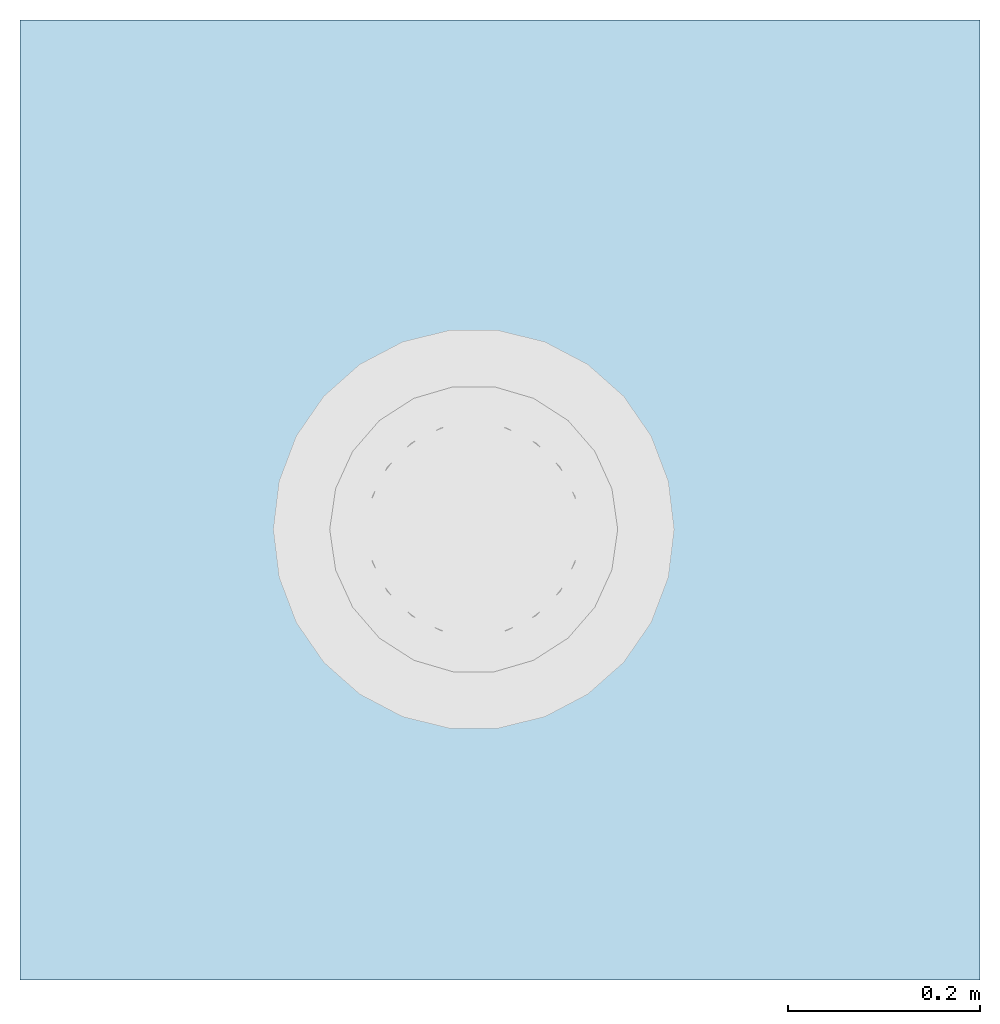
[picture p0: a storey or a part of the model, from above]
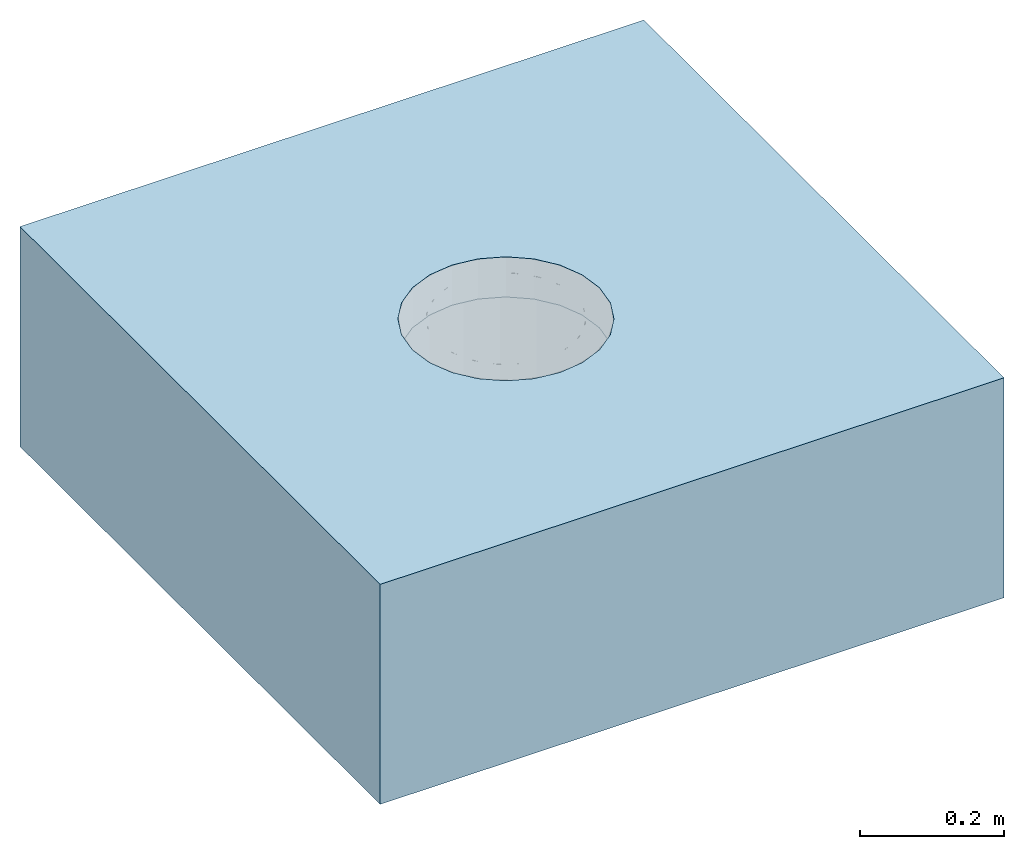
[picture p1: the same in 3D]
Properties of the parts of a building model (IFC2X3)

# File
Description: ViewDefinition [CoordinationView]
File name: Project Number
Time: 2014-10-21T15:01:19
Written by: The EXPRESS Data Manager Version 5.01.0100.02.64mod : 6 Jun 2012
Made in: 20130308_1515(x64) - Exporter 2014.0.2013.0308 - Default UI
Comment: STEP Physical File produced by: The EXPRESS Data Manager Version 5.01.0100.02.64mod : 6 Jun 2012 * Module: EDMstepFileFactory/EDMstandAlone * Creation date: Tue Oct 21 15:01:19 2014 * Host: IN-BLR-PC-0012 * Database: C:\Users\pponnur\AppData\Local\Temp\{F2FFD032-D048-4449-9359-971623433BEB}\ifc * Database version: 5507 * Database creation date: Tue Oct 21 15:01:17 2014 * Schema: IFC2X3 * Model: DataRepository.ifc * Model creation date: Tue Oct 21 15:01:18 2014 * Header model: DataRepository.ifc_HeaderModel * Header model creation date: Tue Oct 21 15:01:18 2014 * EDMuser: sdai-user * EDMgroup: sdai-group * License ID and type: 5605 : Permanent license. Expiry date: * EDMstepFileFactory options: 020000

# IfcProject, Project Number
LongName: Project Name; Phase: Project Status

# IfcSite, Default
RefLatitude: 42, 21, 30, 344238; RefLongitude: -71, -3, -35, -194702; RefElevation: 0 mm

# IfcBuilding
Pset_BuildingCommon - NumberOfStoreys: 1
Other - Project Issue Date: Issue Date; Project Name: Project Name; Project Status: Project Status; Client Name: Owner; Project Address: Enter address here; Project Number: Project Number

# IfcBuildingStorey, Level 1
LongName: Level 1; Elevation: 0 mm
Constraints - Elevation Base: Project Base Point; Elevation: 0 mm
Graphics - Color: 0; Symbol: Level Head - Circle: Level Head - Circle; Line Weight: 1; Symbol at End 1 Default: no; Line Pattern: Grid Line 1/2"; Symbol at End 2 Default: yes
Identity Data - Structural: no; Building Story: yes; Name: Level 1
Dimensions - Computation Height: 0 mm

# IfcFlowTerminal: 408063 Body / 408242 Top - 110mm Dia Outlet, ACO BD Gully 218 Telescopic - Vinyl top - Vertical Outlet with Adhesive Flange - 222 mm:408063 Body / 408242 Top - 110mm Dia Outlet:201730
In: Level 1
Material: Rubber, Nitrile, Stainless Steel AISI 304
Materials and Finishes - Material: Stainless Steel AISI 304
Mechanical - System Classification: Sanitary
Other - Gully Void Start: 0 mm; Floor Void End: -238 mm; 408226 - Raising piece with adhesive bonding flange: no; Raising Piece Detail: no; Raising Piece Position Height: 500 mm; Floor to Gully Height: 68 mm; Vertical 160: no; Gully Top: yes; vertical 110: yes; Grating 250 x 250mm: yes
Model Properties - Raising Piece Product Code 408226: NA; Grating Product Code 97153: Load Class L15 (EN 1253) - Perforated Grating - Plain - Stainless steel 1.4301 (EN 10088) - 222mm Ø; Product Code 408222: Silt Basket - Stainless Steel 304; Product Code 408221: Foul Air Trap Support Ring - Nitrile; Product Code 408220: Foul Air Trap - Stainless Steel 304; Product Code 408225: Friction Ring Installation Set - Nitrile; Grating Product Code 97148: Load Class M125 (EN 1253) - Ladder Grating - Plain - Stainless steel 1.4301 (EN 10088) - 222mm Ø; Grating Product Code 97156: Load Class M125 (EN 1253) - Slot Grating - Plain - Stainless steel 1.4301 (EN 10088) - 222mm Ø
Constraints - Level: Level: Level 1
Construction - 408220 - Foul Air Trap & 408221 - Foul Air Trap Support Ring: yes; 408222 - Silt Basket: yes; 97156 - 222mm Ø - Slot Grating - Plain - Stainless steel 304: yes; 97153 - 222mm Ø - Perforated Grating - Plain - Stainless steel 304: yes; 97148 - 222mm Ø - Ladder Grating - Plain - Stainless steel 304: yes
Dimensions - FFL To Gully Top Height: 68 mm; Square Size: 300 mm; Grating Depth: 30 mm; Outlet: 53.5 mm; Seepage Water Removal Pipe End: -25 mm; Gully Void End: -268 mm; Outlet Height: 98 mm
Identity Data - Mark: 6; Website: www.acobd.com; Telephone: +44 (0)1462 816666; Fax: +44 (0)1462 851490; Watermarked By: www.acobd.com; Water Mark 2: This file is water marked and users are prohibited to reproduce, adapt, distribute this information; Address: ACO Business Centre, Caxton Road, Bedford, MK41 0LF; Manufacturer: ACO Building Drainage; Water Marked With: BIM Manager Premium Suite; E-mail Technical: abdtechnical@aco.co.uk; Water Mark 1: This file is the property of ACO Technologies PLC; E-mail Sales: abdcommercial@aco.co.uk
Phasing - Phase Created: New Construction
Pset_ManufacturerTypeInformation - Manufacturer: ACO Building Drainage
General - Product Standard: EN 1253; Installation guidelines: http://issuu.com/acobuildingdrainage/docs/120820112708-138bdc871b784edfa2b6b8197acfd881?e=0; Foul Air Trap Seal Recyclable: Fully Recyclable; Gully Recyclable: Fully Recyclable; Gully Material: Stainless Steel Grade 304 (EN 1253); Price: POA - contact ACO; Foul Air Trap Seal Colour: Black; Gully Top Product Description: ACO Gully 218 Telescopic Top for Vinyl Floor; Product Range: ACO Gully 218; Gully Colour: passivated stainless steel surface ( matt grey); Maintenance guidelines: http://issuu.com/acobuildingdrainage/docs/120820112708-138bdc871b784edfa2b6b8197acfd881?e=0; NBS Specification: R11 ABOVE GROUND FOUL DRAINAGE SYSTEMS : Clause 315; Product Type: Point Drainage; Gully Top Size (mm): 242mm Diameter; Gully top Grate size (mm): 222; Gully Recycled Material Content: 20 - 30 %; Flow Rate (l/s): 5.0 - 6.3 l/s; Gully Product Code: 408063; Load Class: A15 - C250 (EN 1253); Foul Air Trap Seal Material: NBR; Gully Product Description: ACO Gully 218 Telescopic Flange Type DN110 Vertical with Foul Air Trap; Gully Flange Type: Adhesive; Gully Top Product Code: 408242; Foul Air Trap Seal Recycled Material Content: 0%; Outlet Diameter (mm): 110

# IfcOpeningElement: Recess
In: Level 1
Constraints - Related to Mass: no; Height Offset From Level: 0 mm; Level: Level: Level 1; Room Bounding: yes
Dimensions - Perimeter: 4000 mm; Thickness: 372.8 mm; Volume: 11.653 ft3; Area: 10.7639 ft2
Phasing - Phase Created: New Construction
Structural - Structural: no; Enable Analytical Model: no
Identity Data - Assembly Description: Floor Construction; Assembly Code: B1010
Analytical Properties - Thermal mass: 53301.1; Thermal Resistance (R): 0.641509; Heat Transfer Coefficient (U): 1.55882; Roughness: 3; Absorptance: 0.7
Construction - Default Thickness: 372.8 mm; Function: Interior
Graphics - Coarse Scale Fill Color: 0

# IfcSlab: Floor:Generic - 12", Floor:Generic - 12":184145
In: Level 1
PredefinedType: FLOOR; Material: Plywood, Sheathing 68 mm, Default Floor 304.8 mm
Constraints - Related to Mass: no; Height Offset From Level: 0 mm; Level: Level: Level 1; Room Bounding: yes
Dimensions - Perimeter: 4000 mm; Thickness: 372.8 mm; Volume: 11.653 ft3; Area: 10.7639 ft2
Phasing - Phase Created: New Construction
Structural - Structural: no; Enable Analytical Model: no
Pset_SlabCommon - Reference: Generic - 12"; IsExternal: no; LoadBearing: yes; ThermalTransmittance: 1.55882 kg/K/s3
Identity Data - Assembly Description: Floor Construction; Assembly Code: B1010
Analytical Properties - Thermal mass: 53301.1; Thermal Resistance (R): 0.641509; Heat Transfer Coefficient (U): 1.55882; Roughness: 3; Absorptance: 0.7
Construction - Default Thickness: 372.8 mm; Function: Interior
Graphics - Coarse Scale Fill Color: 0
